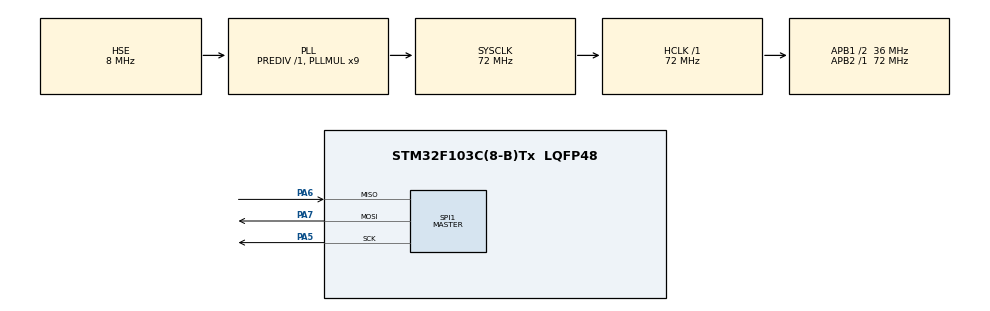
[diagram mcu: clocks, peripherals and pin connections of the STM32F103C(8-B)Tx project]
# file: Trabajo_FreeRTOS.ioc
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Mcu.Family=STM32F1
RCC.PLLSourceVirtual=RCC_PLLSOURCE_HSE
PA6.Mode=Full_Duplex_Master
FREERTOS.Tasks01=defaultTask,0,128,StartDefaultTask,Default,NULL,Dynamic,NULL,NULL
PA7.Mode=Full_Duplex_Master
PD1-OSC_OUT.Mode=HSE-External-Oscillator
SPI1.VirtualType=VM_MASTER
NVIC.TIM1_UP_IRQn=true\:0\:0\:false\:false\:true\:false\:false\:true
PD0-OSC_IN.Signal=RCC_OSC_IN
RCC.APB1CLKDivider=RCC_HCLK_DIV2
RCC.SYSCLKSource=RCC_SYSCLKSOURCE_PLLCLK
ProjectManager.StackSize=0x400
PD1-OSC_OUT.Signal=RCC_OSC_OUT
PA13.Signal=SYS_JTMS-SWDIO
ProjectManager.TargetToolchain=STM32CubeIDE
SPI1.Direction=SPI_DIRECTION_2LINES
RCC.HCLKFreq_Value=72000000
RCC.APB2TimFreq_Value=72000000
RCC.USBFreq_Value=72000000
RCC.AHBFreq_Value=72000000
PD0-OSC_IN.Mode=HSE-External-Oscillator
PA5.Signal=SPI1_SCK
board=custom
RCC.PLLMUL=RCC_PLL_MUL9
RCC.APB2Freq_Value=72000000
SPI1.Mode=SPI_MODE_MASTER
PA14.Mode=Serial_Wire
VP_SYS_VS_tim1.Mode=TIM1
VP_FREERTOS_VS_CMSIS_V1.Mode=CMSIS_V1
PA13.Mode=Serial_Wire
Mcu.Name=STM32F103C(8-B)Tx
RCC.SYSCLKFreq_VALUE=72000000
Mcu.Package=LQFP48
PA6.Signal=SPI1_MISO
NVIC.TimeBase=TIM1_UP_IRQn
NVIC.TimeBaseIP=TIM1
PA14.Signal=SYS_JTCK-SWCLK
ProjectManager.HeapSize=0x200
NVIC.PriorityGroup=NVIC_PRIORITYGROUP_4
RCC.APB1TimFreq_Value=72000000
RCC.APB1Freq_Value=36000000
PA5.Mode=Full_Duplex_Master
PA7.Signal=SPI1_MOSI

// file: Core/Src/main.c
/* USER CODE BEGIN Header */
/**
  ******************************************************************************
  * @file           : main.c
  * @brief          : Main program body
  ******************************************************************************
  * @attention
  *
  * <h2><center>&copy; Copyright (c) 2021 STMicroelectronics.
  * All rights reserved.</center></h2>
  *
  * This software component is licensed by ST under BSD 3-Clause license,
  * the "License"; You may not use this file except in compliance with the
  * License. You may obtain a copy of the License at:
  *                        opensource.org/licenses/BSD-3-Clause
  *
  ******************************************************************************
  */
/* USER CODE END Header */
#include "main.h"

SPI_HandleTypeDef hspi1;

osThreadId defaultTaskHandle;

void SystemClock_Config(void);
static void MX_GPIO_Init(void);
static void MX_SPI1_Init(void);
void StartDefaultTask(void const * argument);

/* USER CODE BEGIN 0 */
board_t mainBoard;
datos_t data;

/* USER CODE END 0 */

int main(void)
{
	/* USER CODE BEGIN 1 */
	// Board principal.

	data.board = &mainBoard;

	clearBoard(data.board);

	/* USER CODE END 1 */

	/* MCU Configuration--------------------------------------------------------*/

	/* Reset of all peripherals, Initializes the Flash interface and the Systick. */
	HAL_Init();

	/* Configure the system clock */
	SystemClock_Config();

	/* Initialize all configured peripherals */
	MX_GPIO_Init();
	MX_SPI1_Init();
	/* USER CODE BEGIN 2 */

	HAL_Delay(500);
	inicializar_max7219(&hspi1, GPIOA, GPIO_PIN_4);

	/* USER CODE END 2 */

	/* USER CODE BEGIN RTOS_SEMAPHORES */
	// Semáforo para mutua exclusión.
	xSemaphoreHandle sem_mutex;

	//Creo un mutex.
	if(!(sem_mutex = xSemaphoreCreateMutex()))
	{
		while(1){
			// Should not reach this point.
		}
	}
	data.mutex = sem_mutex;
	/* USER CODE END RTOS_SEMAPHORES */

	/* Create the thread(s) */
	/* definition and creation of defaultTask */

	// Creamos las tareas

	osThreadDef(defaultTask, StartDefaultTask, osPriorityNormal, 0, 128);
	defaultTaskHandle = osThreadCreate(osThread(defaultTask), NULL);

	if( xTaskCreate(updateBoardTask,
					"UpdateBoard Task",
					2*configMINIMAL_STACK_SIZE,
					&data,
					tskIDLE_PRIORITY+1,
					NULL) != pdPASS)

	/* USER CODE BEGIN RTOS_THREADS */

	{
		while(1){
					// Should not reach this point.
				}
	}

	if( xTaskCreate(checkStatusTask,
						"CheckStatus Task",
						2*configMINIMAL_STACK_SIZE,
						&data,
						tskIDLE_PRIORITY+2,
						NULL) != pdPASS)
	{
		while(1){
					// Should not reach this point.
				}
	}

	/* USER CODE END RTOS_THREADS */

	/* Start scheduler */
	osKernelStart();

// =========================================================================
	/* We should never get here as control is now taken by the scheduler */

	/* Infinite loop */
	while (1)
	{

	}
}

void SystemClock_Config(void)
{
  RCC_OscInitTypeDef RCC_OscInitStruct = {0};
  RCC_ClkInitTypeDef RCC_ClkInitStruct = {0};

  /** Initializes the RCC Oscillators according to the specified parameters
  * in the RCC_OscInitTypeDef structure.
  */
  RCC_OscInitStruct.OscillatorType = RCC_OSCILLATORTYPE_HSE;
  RCC_OscInitStruct.HSEState = RCC_HSE_ON;
  RCC_OscInitStruct.HSEPredivValue = RCC_HSE_PREDIV_DIV1;
  RCC_OscInitStruct.HSIState = RCC_HSI_ON;
  RCC_OscInitStruct.PLL.PLLState = RCC_PLL_ON;
  RCC_OscInitStruct.PLL.PLLSource = RCC_PLLSOURCE_HSE;
  RCC_OscInitStruct.PLL.PLLMUL = RCC_PLL_MUL9;
  if (HAL_RCC_OscConfig(&RCC_OscInitStruct) != HAL_OK)
  {
    Error_Handler();
  }
  /** Initializes the CPU, AHB and APB buses clocks
  */
  RCC_ClkInitStruct.ClockType = RCC_CLOCKTYPE_HCLK|RCC_CLOCKTYPE_SYSCLK
                              |RCC_CLOCKTYPE_PCLK1|RCC_CLOCKTYPE_PCLK2;
  RCC_ClkInitStruct.SYSCLKSource = RCC_SYSCLKSOURCE_PLLCLK;
  RCC_ClkInitStruct.AHBCLKDivider = RCC_SYSCLK_DIV1;
  RCC_ClkInitStruct.APB1CLKDivider = RCC_HCLK_DIV2;
  RCC_ClkInitStruct.APB2CLKDivider = RCC_HCLK_DIV1;

  if (HAL_RCC_ClockConfig(&RCC_ClkInitStruct, FLASH_LATENCY_2) != HAL_OK)
  {
    Error_Handler();
  }
}

static void MX_SPI1_Init(void)
{

  /* SPI1 parameter configuration*/
  hspi1.Instance = SPI1;
  hspi1.Init.Mode = SPI_MODE_MASTER;
  hspi1.Init.Direction = SPI_DIRECTION_2LINES;
  hspi1.Init.DataSize = SPI_DATASIZE_16BIT;
  hspi1.Init.CLKPolarity = SPI_POLARITY_LOW;
  hspi1.Init.CLKPhase = SPI_PHASE_1EDGE;
  hspi1.Init.NSS = SPI_NSS_SOFT;
  hspi1.Init.BaudRatePrescaler = SPI_BAUDRATEPRESCALER_16;
  hspi1.Init.FirstBit = SPI_FIRSTBIT_MSB;
  hspi1.Init.TIMode = SPI_TIMODE_DISABLE;
  hspi1.Init.CRCCalculation = SPI_CRCCALCULATION_DISABLE;
  hspi1.Init.CRCPolynomial = 10;
  if (HAL_SPI_Init(&hspi1) != HAL_OK)
  {
    Error_Handler();
  }

}

static void MX_GPIO_Init(void)
{
  GPIO_InitTypeDef GPIO_InitStruct = {0};

  /* GPIO Ports Clock Enable */
  __HAL_RCC_GPIOC_CLK_ENABLE();
  __HAL_RCC_GPIOD_CLK_ENABLE();
  __HAL_RCC_GPIOA_CLK_ENABLE();

  /*Configure GPIO pin Output Level */
  HAL_GPIO_WritePin(GPIOC, GPIO_PIN_13, GPIO_PIN_RESET);

  /*Configure GPIO pin Output Level */
  HAL_GPIO_WritePin(GPIOA, GPIO_PIN_4, GPIO_PIN_RESET);

  /*Configure GPIO pin : PC13 */
  GPIO_InitStruct.Pin = GPIO_PIN_13;
  GPIO_InitStruct.Mode = GPIO_MODE_OUTPUT_PP;
  GPIO_InitStruct.Pull = GPIO_NOPULL;
  GPIO_InitStruct.Speed = GPIO_SPEED_FREQ_LOW;
  HAL_GPIO_Init(GPIOC, &GPIO_InitStruct);

  /*Configure GPIO pin : PA4 */
  GPIO_InitStruct.Pin = GPIO_PIN_4;
  GPIO_InitStruct.Mode = GPIO_MODE_OUTPUT_PP;
  GPIO_InitStruct.Pull = GPIO_NOPULL;
  GPIO_InitStruct.Speed = GPIO_SPEED_FREQ_LOW;
  HAL_GPIO_Init(GPIOA, &GPIO_InitStruct);

}

void StartDefaultTask(void const * argument)
{
  for(;;)
  {
    osDelay(1);
  }
}

 /**
  * @brief  Period elapsed callback in non blocking mode
  * @note   This function is called  when TIM1 interrupt took place, inside
  * HAL_TIM_IRQHandler(). It makes a direct call to HAL_IncTick() to increment
  * a global variable "uwTick" used as application time base.
  * @param  htim : TIM handle
  * @retval None
  */
void HAL_TIM_PeriodElapsedCallback(TIM_HandleTypeDef *htim)
{
  if (htim->Instance == TIM1) {
    HAL_IncTick();
  }
}

void Error_Handler(void)
{
  __disable_irq();
  while (1)
  {
  }
}

/************************ (C) COPYRIGHT STMicroelectronics *****END OF FILE****/
